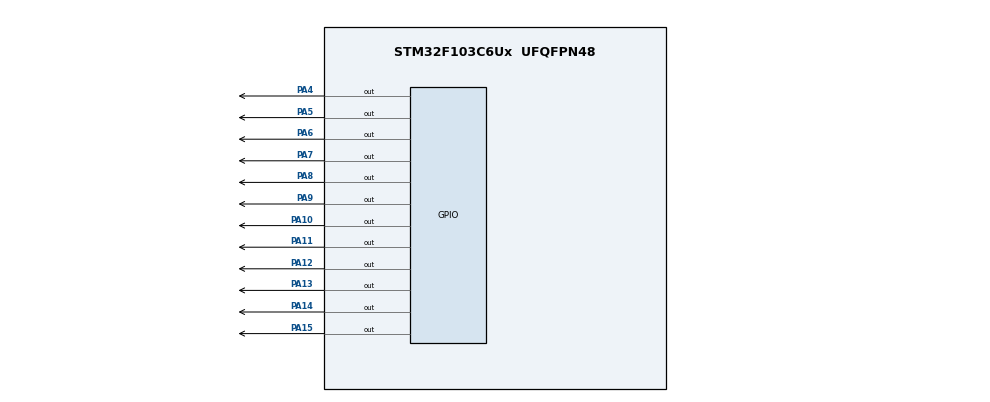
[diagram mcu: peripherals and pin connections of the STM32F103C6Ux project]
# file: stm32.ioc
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Mcu.Family=STM32F1
Mcu.Name=STM32F103C6Ux
Mcu.Package=UFQFPN48
NVIC.PriorityGroup=NVIC_PRIORITYGROUP_4
PA10.Signal=GPIO_Output
PA11.Signal=GPIO_Output
PA12.Signal=GPIO_Output
PA13.Signal=GPIO_Output
PA14.Signal=GPIO_Output
PA15.Signal=GPIO_Output
PA4.Signal=GPIO_Output
PA5.Signal=GPIO_Output
PA6.Signal=GPIO_Output
PA7.Signal=GPIO_Output
PA8.Signal=GPIO_Output
PA9.Signal=GPIO_Output
ProjectManager.HeapSize=0x200
ProjectManager.StackSize=0x400
ProjectManager.TargetToolchain=STM32CubeIDE
RCC.APB1Freq_Value=8000000
RCC.APB2Freq_Value=8000000
board=custom

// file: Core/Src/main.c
/* USER CODE BEGIN Header */
/**
  ******************************************************************************
  * @file           : main.c
  * @brief          : Main program body
  ******************************************************************************
  * @attention
  *
  * Copyright (c) 2023 STMicroelectronics.
  * All rights reserved.
  *
  * This software is licensed under terms that can be found in the LICENSE file
  * in the root directory of this software component.
  * If no LICENSE file comes with this software, it is provided AS-IS.
  *
  ******************************************************************************
  */
/* USER CODE END Header */
#include "main.h"

void SystemClock_Config(void);
static void MX_GPIO_Init(void);

/* USER CODE BEGIN 0 */
void display7SEG(int num) {
   // Turn off all segments
   // Define the segments for each number (0-9)
   if(num == 0)
   {
   	HAL_GPIO_WritePin(GPIOB, a_Pin, RESET);
   	HAL_GPIO_WritePin(GPIOB, b_Pin, RESET);
   	HAL_GPIO_WritePin(GPIOB, c_Pin, RESET);
   	HAL_GPIO_WritePin(GPIOB, d_Pin, RESET);
   	HAL_GPIO_WritePin(GPIOB, e_Pin, RESET);
   	HAL_GPIO_WritePin(GPIOB, f_Pin, RESET);
   	HAL_GPIO_WritePin(GPIOB, g_Pin, SET);
   }
   else if( num == 1)
   {
   	HAL_GPIO_WritePin(GPIOB, a_Pin, SET);
		HAL_GPIO_WritePin(GPIOB, b_Pin, RESET);
		HAL_GPIO_WritePin(GPIOB, c_Pin, RESET);
		HAL_GPIO_WritePin(GPIOB, d_Pin, SET);
		HAL_GPIO_WritePin(GPIOB, e_Pin, SET);
		HAL_GPIO_WritePin(GPIOB, f_Pin, SET);
		HAL_GPIO_WritePin(GPIOB, g_Pin, SET);
   }
   else if (num == 2)
   {
   	HAL_GPIO_WritePin(GPIOB, a_Pin, RESET);
		HAL_GPIO_WritePin(GPIOB, b_Pin, RESET);
		HAL_GPIO_WritePin(GPIOB, c_Pin, SET);
		HAL_GPIO_WritePin(GPIOB, d_Pin, RESET);
		HAL_GPIO_WritePin(GPIOB, e_Pin, RESET);
		HAL_GPIO_WritePin(GPIOB, f_Pin, SET);
		HAL_GPIO_WritePin(GPIOB, g_Pin, RESET);
   }
   else if (num == 3)
   {
   	HAL_GPIO_WritePin(GPIOB, a_Pin, RESET);
		HAL_GPIO_WritePin(GPIOB, b_Pin, RESET);
		HAL_GPIO_WritePin(GPIOB, c_Pin, RESET);
		HAL_GPIO_WritePin(GPIOB, d_Pin, RESET);
		HAL_GPIO_WritePin(GPIOB, e_Pin, SET);
		HAL_GPIO_WritePin(GPIOB, f_Pin, SET);
		HAL_GPIO_WritePin(GPIOB, g_Pin, RESET);
   }
   else if (num == 4)
   {
   	HAL_GPIO_WritePin(GPIOB, a_Pin, SET);
		HAL_GPIO_WritePin(GPIOB, b_Pin, RESET);
		HAL_GPIO_WritePin(GPIOB, c_Pin, RESET);
		HAL_GPIO_WritePin(GPIOB, d_Pin, SET);
		HAL_GPIO_WritePin(GPIOB, e_Pin, SET);
		HAL_GPIO_WritePin(GPIOB, f_Pin, RESET);
		HAL_GPIO_WritePin(GPIOB, g_Pin, RESET);
   }
   else if (num == 5)
   {
   	HAL_GPIO_WritePin(GPIOB, a_Pin, RESET);
		HAL_GPIO_WritePin(GPIOB, b_Pin, SET);
		HAL_GPIO_WritePin(GPIOB, c_Pin, RESET);
		HAL_GPIO_WritePin(GPIOB, d_Pin, RESET);
		HAL_GPIO_WritePin(GPIOB, e_Pin, SET);
		HAL_GPIO_WritePin(GPIOB, f_Pin, RESET);
		HAL_GPIO_WritePin(GPIOB, g_Pin, RESET);
   }
   else if (num == 6)
   {
   	HAL_GPIO_WritePin(GPIOB, a_Pin, RESET);
		HAL_GPIO_WritePin(GPIOB, b_Pin, SET);
		HAL_GPIO_WritePin(GPIOB, c_Pin, RESET);
		HAL_GPIO_WritePin(GPIOB, d_Pin, RESET);
		HAL_GPIO_WritePin(GPIOB, e_Pin, RESET);
		HAL_GPIO_WritePin(GPIOB, f_Pin, RESET);
		HAL_GPIO_WritePin(GPIOB, g_Pin, RESET);
   }
   else if (num == 7)
   {
   	HAL_GPIO_WritePin(GPIOB, a_Pin, RESET);
		HAL_GPIO_WritePin(GPIOB, b_Pin, RESET);
		HAL_GPIO_WritePin(GPIOB, c_Pin, RESET);
		HAL_GPIO_WritePin(GPIOB, d_Pin, SET);
		HAL_GPIO_WritePin(GPIOB, e_Pin, SET);
		HAL_GPIO_WritePin(GPIOB, f_Pin, SET);
		HAL_GPIO_WritePin(GPIOB, g_Pin, SET);
   }
   else if (num == 8)
   {
   	HAL_GPIO_WritePin(GPIOB, a_Pin, RESET);
		HAL_GPIO_WritePin(GPIOB, b_Pin, RESET);
		HAL_GPIO_WritePin(GPIOB, c_Pin, RESET);
		HAL_GPIO_WritePin(GPIOB, d_Pin, RESET);
		HAL_GPIO_WritePin(GPIOB, e_Pin, RESET);
		HAL_GPIO_WritePin(GPIOB, f_Pin, RESET);
		HAL_GPIO_WritePin(GPIOB, g_Pin, RESET);
   }
   else if (num == 9)
   {
   	HAL_GPIO_WritePin(GPIOB, a_Pin, RESET);
		HAL_GPIO_WritePin(GPIOB, b_Pin, RESET);
		HAL_GPIO_WritePin(GPIOB, c_Pin, RESET);
		HAL_GPIO_WritePin(GPIOB, d_Pin, RESET);
		HAL_GPIO_WritePin(GPIOB, e_Pin, SET);
		HAL_GPIO_WritePin(GPIOB, f_Pin, RESET);
		HAL_GPIO_WritePin(GPIOB, g_Pin, RESET);
   }
}

/* USER CODE END 0 */

int main(void)
{

  /* MCU Configuration--------------------------------------------------------*/

  /* Reset of all peripherals, Initializes the Flash interface and the Systick. */
  HAL_Init();

  /* Configure the system clock */
  SystemClock_Config();

  /* Initialize all configured peripherals */
  MX_GPIO_Init();

  /* Infinite loop */
  /* USER CODE BEGIN WHILE */
	int count= 0;
  while (1)
   {
	 if(count > 9) count = 0;
	 display7SEG(count);
	 count ++;
	 HAL_Delay(1000);
    /* USER CODE END WHILE */

    }
}

void SystemClock_Config(void)
{
  RCC_OscInitTypeDef RCC_OscInitStruct = {0};
  RCC_ClkInitTypeDef RCC_ClkInitStruct = {0};

  /** Initializes the RCC Oscillators according to the specified parameters
  * in the RCC_OscInitTypeDef structure.
  */
  RCC_OscInitStruct.OscillatorType = RCC_OSCILLATORTYPE_HSI;
  RCC_OscInitStruct.HSIState = RCC_HSI_ON;
  RCC_OscInitStruct.HSICalibrationValue = RCC_HSICALIBRATION_DEFAULT;
  RCC_OscInitStruct.PLL.PLLState = RCC_PLL_NONE;
  if (HAL_RCC_OscConfig(&RCC_OscInitStruct) != HAL_OK)
  {
    Error_Handler();
  }

  /** Initializes the CPU, AHB and APB buses clocks
  */
  RCC_ClkInitStruct.ClockType = RCC_CLOCKTYPE_HCLK|RCC_CLOCKTYPE_SYSCLK
                              |RCC_CLOCKTYPE_PCLK1|RCC_CLOCKTYPE_PCLK2;
  RCC_ClkInitStruct.SYSCLKSource = RCC_SYSCLKSOURCE_HSI;
  RCC_ClkInitStruct.AHBCLKDivider = RCC_SYSCLK_DIV1;
  RCC_ClkInitStruct.APB1CLKDivider = RCC_HCLK_DIV1;
  RCC_ClkInitStruct.APB2CLKDivider = RCC_HCLK_DIV1;

  if (HAL_RCC_ClockConfig(&RCC_ClkInitStruct, FLASH_LATENCY_0) != HAL_OK)
  {
    Error_Handler();
  }
}

static void MX_GPIO_Init(void)
{
  GPIO_InitTypeDef GPIO_InitStruct = {0};

  /* GPIO Ports Clock Enable */
  __HAL_RCC_GPIOA_CLK_ENABLE();
  __HAL_RCC_GPIOB_CLK_ENABLE();

  /*Configure GPIO pin Output Level */
  HAL_GPIO_WritePin(GPIOA, LED_RED_Pin|LED_YELLOW_Pin|LED_GREEN_Pin|LED_RED2_Pin
                          |LED_YELLOW2_Pin|LED_GREEN2_Pin, GPIO_PIN_RESET);

  /*Configure GPIO pin Output Level */
  HAL_GPIO_WritePin(GPIOB, a_Pin|b_Pin|c_Pin|d_Pin
                          |e_Pin|f_Pin|g_Pin, GPIO_PIN_RESET);

  /*Configure GPIO pins : LED_RED_Pin LED_YELLOW_Pin LED_GREEN_Pin LED_RED2_Pin
                           LED_YELLOW2_Pin LED_GREEN2_Pin */
  GPIO_InitStruct.Pin = LED_RED_Pin|LED_YELLOW_Pin|LED_GREEN_Pin|LED_RED2_Pin
                          |LED_YELLOW2_Pin|LED_GREEN2_Pin;
  GPIO_InitStruct.Mode = GPIO_MODE_OUTPUT_PP;
  GPIO_InitStruct.Pull = GPIO_NOPULL;
  GPIO_InitStruct.Speed = GPIO_SPEED_FREQ_LOW;
  HAL_GPIO_Init(GPIOA, &GPIO_InitStruct);

  /*Configure GPIO pins : a_Pin b_Pin c_Pin d_Pin
                           e_Pin f_Pin g_Pin */
  GPIO_InitStruct.Pin = a_Pin|b_Pin|c_Pin|d_Pin
                          |e_Pin|f_Pin|g_Pin;
  GPIO_InitStruct.Mode = GPIO_MODE_OUTPUT_PP;
  GPIO_InitStruct.Pull = GPIO_NOPULL;
  GPIO_InitStruct.Speed = GPIO_SPEED_FREQ_LOW;
  HAL_GPIO_Init(GPIOB, &GPIO_InitStruct);

}

void Error_Handler(void)
{
  __disable_irq();
  while (1)
  {
  }
}
